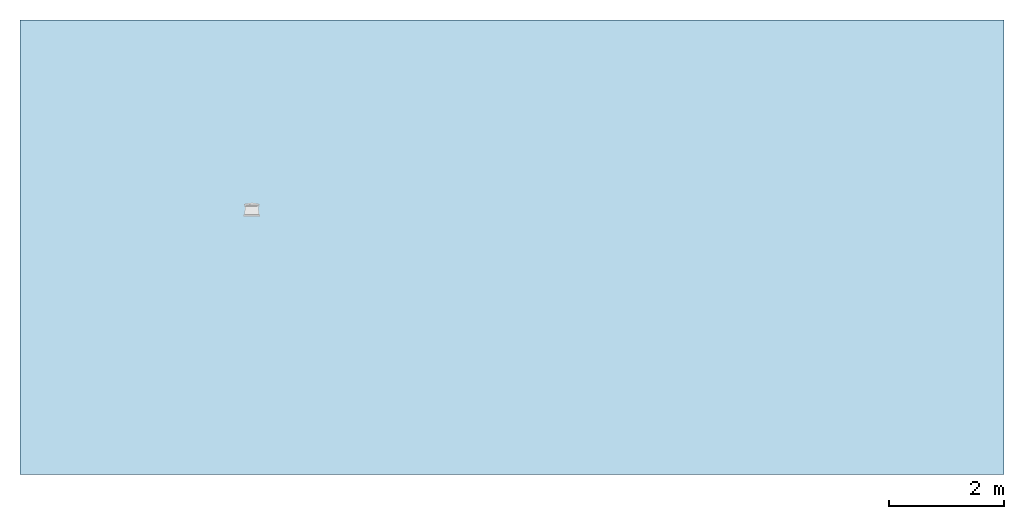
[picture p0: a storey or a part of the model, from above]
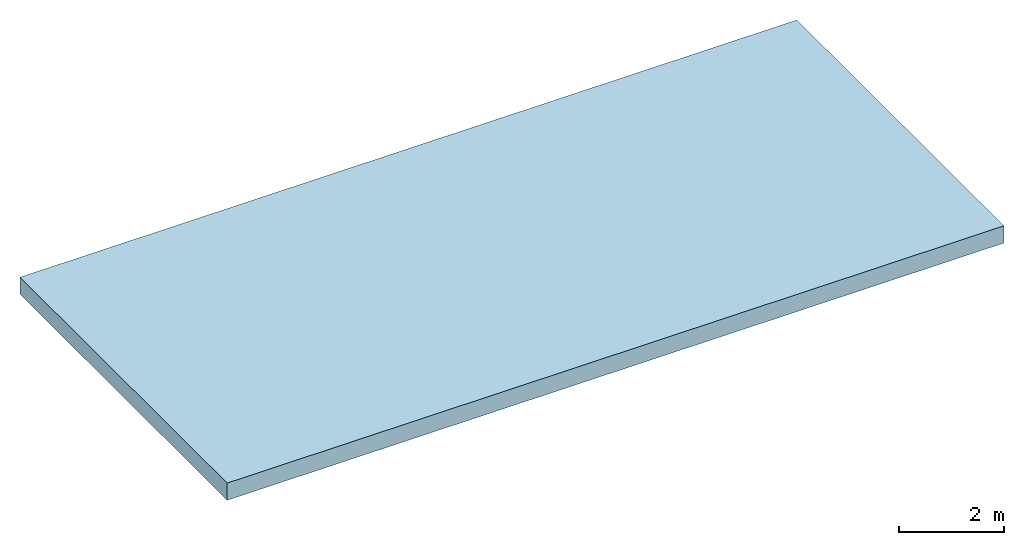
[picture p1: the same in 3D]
Properties of the parts of a building model (IFC2X3)

# File
Description: ViewDefinition [CoordinationView]
File name: 42221 - Multi-functional End Cap (at Male end).ifc
Time: 2013-07-12T09:08:57
Written by: Autodesk Revit 2013
Made in: 20120221_2030(x64)

# IfcProject, Project Number
LongName: Project Name; Phase: Project Status

# IfcSite, Default
RefLatitude: 42, 21, 30, 344238; RefLongitude: -71, -3, -35, -194702; RefElevation: 0 mm

# IfcBuilding
Pset_BuildingCommon - NumberOfStoreys: 1
Other - Project Number: Project Number; Client Name: Owner; Project Status: Project Status; Project Name: Project Name; Project Address: ## Street City, State Zip; Project Issue Date: Issue Date

# IfcBuildingStorey, Level 1
LongName: Level 1; Elevation: 0 mm
Constraints - Elevation Base: 0; Elevation: 0 mm
Graphics - Symbol: M_Level Head - Circle: M_Level Head - Circle; Color: 0; Symbol at End 1 Default: no; Line Pattern: Center; Line Weight: 1; Symbol at End 2 Default: yes
Dimensions - Computation Height: 0 mm
Identity Data - Building Story: yes; Name: Level 1; Structural: no

# IfcBuildingElementProxy: Male end cap, Male end cap:Male end cap:Male end cap:521879
In: Level 1
Constraints - Moves With Nearby Elements: no; Level: Level: Level 1
Dimensions - Volume: 2403709 mm3; Centre_Depth: 414.5 mm
Phasing - Phase Created: New Construction
Pset_BuildingElementProxyCommon - Reference: Male end cap

# IfcOpeningElement: Recess
In: Level 1
Constraints - Height Offset From Level: 0 mm; Room Bounding: yes; Level: Level: Level 1; Related to Mass: no
Structural - Enable Analytical Model: no; Structural: no
Dimensions - Volume: 54027021352 mm3; Thickness: 400 mm; Area: 135090000 mm2; Perimeter: 50000 mm
Phasing - Phase Created: New Construction
Graphics - Coarse Scale Fill Color: 0
Analytical Properties - Absorptance: 0.1; Roughness: 1
Materials and Finishes - Structural Material: Plant
Construction - Default Thickness: 400 mm; Function: 0

# IfcSlab: Floor:Generic Floor - 400mm, Floor:Generic Floor - 400mm:193825
In: Level 1
PredefinedType: FLOOR; Material: Plant 400 mm
Constraints - Height Offset From Level: 0 mm; Room Bounding: yes; Level: Level: Level 1; Related to Mass: no
Structural - Enable Analytical Model: no; Structural: no
Dimensions - Volume: 54027021352 mm3; Thickness: 400 mm; Area: 135090000 mm2; Perimeter: 50000 mm
Phasing - Phase Created: New Construction
Pset_SlabCommon - Reference: Generic Floor - 400mm; IsExternal: no; LoadBearing: yes
Graphics - Coarse Scale Fill Color: 0
Analytical Properties - Absorptance: 0.1; Roughness: 1
Materials and Finishes - Structural Material: Plant
Construction - Default Thickness: 400 mm; Function: 0
